One B-rep face of a CAD part: STEP entity #365.
In plain terms, the planar face has unit normal (1, 0, 0).
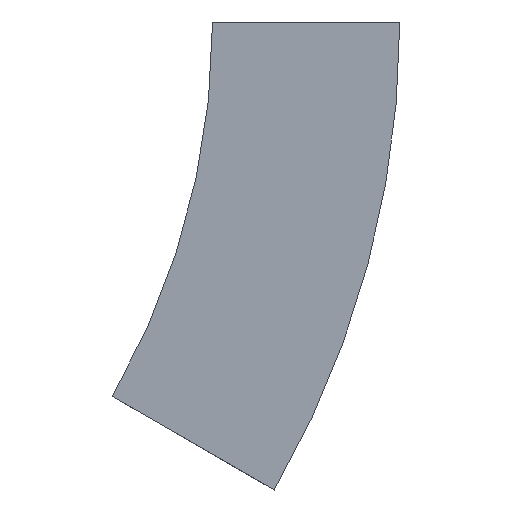
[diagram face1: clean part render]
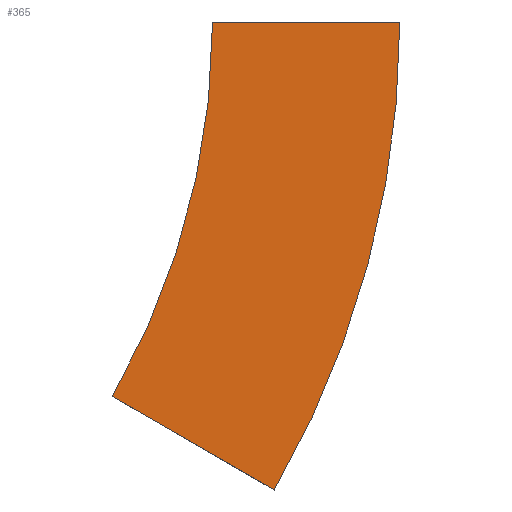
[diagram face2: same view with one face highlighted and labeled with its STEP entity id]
Its self-contained STEP definition (entity closure, numbers rounded to 3 decimals):
#3 = DIRECTION ( 'NONE',  ( 1., 0., 0. ) ) ;
#11 = DIRECTION ( 'NONE',  ( 0., 0.866, 0.5 ) ) ;
#54 = VERTEX_POINT ( 'NONE', #178 ) ;
#71 = ORIENTED_EDGE ( 'NONE', *, *, #464, .T. ) ;
#75 = CIRCLE ( 'NONE', #86, 300. ) ;
#86 = AXIS2_PLACEMENT_3D ( 'NONE', #217, #3, #303 ) ;
#90 = LINE ( 'NONE', #267, #295 ) ;
#149 = CIRCLE ( 'NONE', #224, 375. ) ;
#159 = ORIENTED_EDGE ( 'NONE', *, *, #287, .T. ) ;
#165 = CARTESIAN_POINT ( 'NONE',  ( 0., -75., 0. ) ) ;
#168 = AXIS2_PLACEMENT_3D ( 'NONE', #348, #484, #444 ) ;
#170 = CARTESIAN_POINT ( 'NONE',  ( 0., -24.76, -187.5 ) ) ;
#178 = CARTESIAN_POINT ( 'NONE',  ( 0., 0., 0. ) ) ;
#180 = EDGE_CURVE ( 'NONE', #545, #54, #243, .T. ) ;
#213 = PLANE ( 'NONE',  #168 ) ;
#217 = CARTESIAN_POINT ( 'NONE',  ( 0., 300., 0. ) ) ;
#224 = AXIS2_PLACEMENT_3D ( 'NONE', #487, #279, #315 ) ;
#236 = VERTEX_POINT ( 'NONE', #288 ) ;
#243 = LINE ( 'NONE', #165, #341 ) ;
#267 = CARTESIAN_POINT ( 'NONE',  ( 0., -24.76, -187.5 ) ) ;
#279 = DIRECTION ( 'NONE',  ( 1., 0., 0. ) ) ;
#287 = EDGE_CURVE ( 'NONE', #372, #236, #90, .T. ) ;
#288 = CARTESIAN_POINT ( 'NONE',  ( 0., 40.192, -150. ) ) ;
#295 = VECTOR ( 'NONE', #11, 1000. ) ;
#303 = DIRECTION ( 'NONE',  ( 0., -1., 0. ) ) ;
#315 = DIRECTION ( 'NONE',  ( 0., -1., 0. ) ) ;
#327 = DIRECTION ( 'NONE',  ( 0., 1., 0. ) ) ;
#341 = VECTOR ( 'NONE', #327, 1000. ) ;
#348 = CARTESIAN_POINT ( 'NONE',  ( 0., -75., 0. ) ) ;
#365 = ADVANCED_FACE ( 'NONE', ( #533 ), #213, .F. ) ;
#372 = VERTEX_POINT ( 'NONE', #170 ) ;
#409 = EDGE_CURVE ( 'NONE', #54, #236, #75, .T. ) ;
#422 = ORIENTED_EDGE ( 'NONE', *, *, #180, .F. ) ;
#424 = EDGE_LOOP ( 'NONE', ( #542, #422, #71, #159 ) ) ;
#444 = DIRECTION ( 'NONE',  ( 0., 0., 1. ) ) ;
#464 = EDGE_CURVE ( 'NONE', #545, #372, #149, .T. ) ;
#484 = DIRECTION ( 'NONE',  ( -1., 0., 0. ) ) ;
#487 = CARTESIAN_POINT ( 'NONE',  ( 0., 300., 0. ) ) ;
#533 = FACE_OUTER_BOUND ( 'NONE', #424, .T. ) ;
#542 = ORIENTED_EDGE ( 'NONE', *, *, #409, .F. ) ;
#545 = VERTEX_POINT ( 'NONE', #560 ) ;
#560 = CARTESIAN_POINT ( 'NONE',  ( 0., -75., 0. ) ) ;
